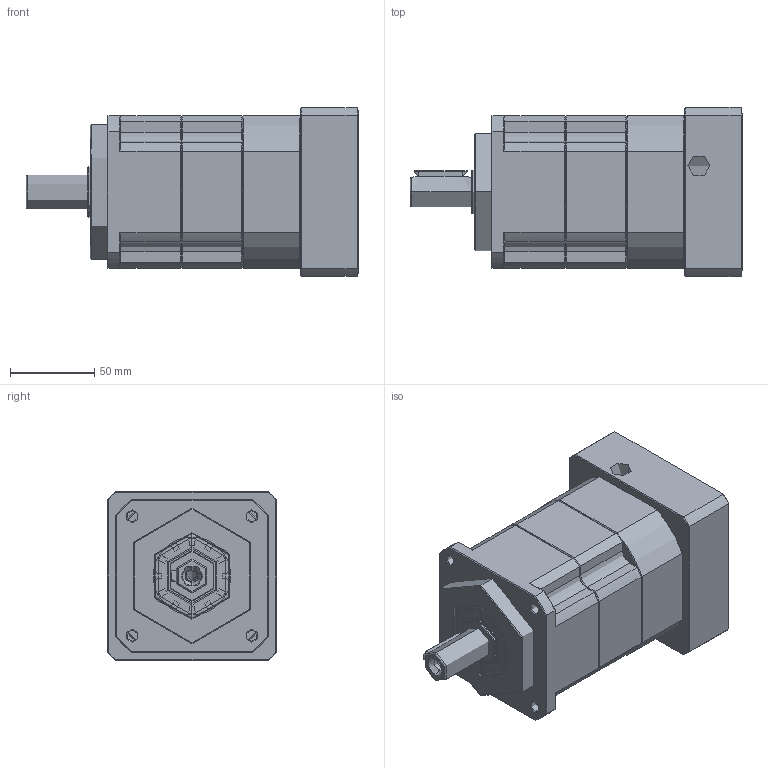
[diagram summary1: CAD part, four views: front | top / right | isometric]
STEP (ISO 10303-21) file: header records copied from the file, then geometry measured from it (millimetres).
FILE_DESCRIPTION (( 'STEP AP214' ), '1' );
FILE_NAME ('ZPB090-D20-L2-P1-19-95-115-M8.step', '2024-06-07T18:16:02', ( 'Windows 蚚誧' ), ( 'Organization' ), 'SwSTEP 2.0', 'SolidWorks 2016', '' );
FILE_SCHEMA (( 'AUTOMOTIVE_DESIGN' ));
Length unit declared in the file: millimetre
Products named in the file (1): ZPB090-D20-L2-P1-19-95-115-M8
Bounding box: 196.5 x 100 x 100 mm (x, y, z)
Topology: 0 solids, 37 shells, 1885 faces, 4977 edges, 3157 vertices
Faces by surface type: plane 969, bspline 387, cone 291, cylinder 236, torus 2
Full cylindrical faces by diameter (mm): 6.72 x1
Entity records: 96355 total; most frequent: CARTESIAN_POINT 48008, ORIENTED_EDGE 9905, DIRECTION 7691, EDGE_CURVE 4973, VECTOR 3273, LINE 3273, VERTEX_POINT 3155, AXIS2_PLACEMENT_3D 2209
One B-rep face of a CAD part: STEP entity #84038.
In plain terms, the planar face has unit normal (-1, 0, 0).
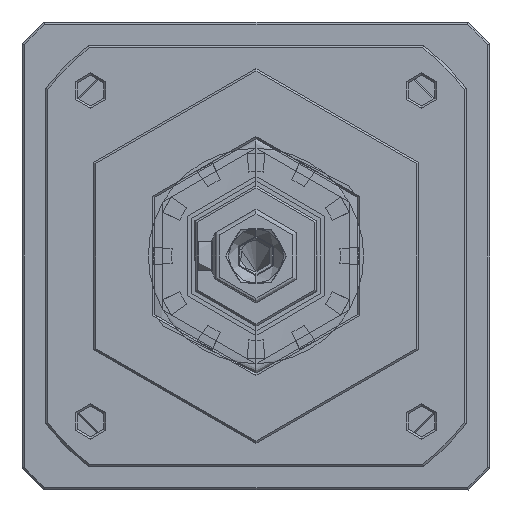
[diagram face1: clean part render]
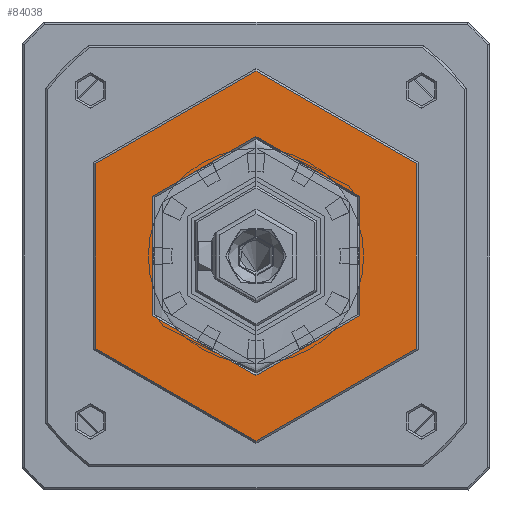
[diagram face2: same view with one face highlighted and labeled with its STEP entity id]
Its self-contained STEP definition (entity closure, numbers rounded to 3 decimals):
#39 = CARTESIAN_POINT ( 'NONE',  ( 0., 0., 25.5 ) ) ;
#2751 = DIRECTION ( 'NONE',  ( 0., 0., -1. ) ) ;
#6170 = CARTESIAN_POINT ( 'NONE',  ( 0., 0., -25.5 ) ) ;
#6382 = DIRECTION ( 'NONE',  ( 0., 0., -1. ) ) ;
#7079 = AXIS2_PLACEMENT_3D ( 'NONE', #30345, #38908, #76479 ) ;
#9382 = DIRECTION ( 'NONE',  ( -1., 0., 0. ) ) ;
#13712 = CARTESIAN_POINT ( 'NONE',  ( 0., 0., 0. ) ) ;
#15279 = EDGE_CURVE ( 'NONE', #36088, #32370, #39493, .T. ) ;
#15583 = CIRCLE ( 'NONE', #60520, 25.5 ) ;
#21239 = CARTESIAN_POINT ( 'NONE',  ( 0., -39.974, 39.974 ) ) ;
#21882 = EDGE_LOOP ( 'NONE', ( #38857, #82229 ) ) ;
#28915 = CARTESIAN_POINT ( 'NONE',  ( 0., 0., 0. ) ) ;
#29334 = EDGE_LOOP ( 'NONE', ( #42366, #30642 ) ) ;
#30345 = CARTESIAN_POINT ( 'NONE',  ( 0., 0., 0. ) ) ;
#30642 = ORIENTED_EDGE ( 'NONE', *, *, #73878, .F. ) ;
#32370 = VERTEX_POINT ( 'NONE', #82319 ) ;
#35837 = DIRECTION ( 'NONE',  ( 0., 0., -1. ) ) ;
#36088 = VERTEX_POINT ( 'NONE', #38172 ) ;
#38172 = CARTESIAN_POINT ( 'NONE',  ( 0., 0., -39.5 ) ) ;
#38857 = ORIENTED_EDGE ( 'NONE', *, *, #15279, .T. ) ;
#38908 = DIRECTION ( 'NONE',  ( -1., 0., 0. ) ) ;
#39493 = CIRCLE ( 'NONE', #45821, 39.5 ) ;
#42366 = ORIENTED_EDGE ( 'NONE', *, *, #92122, .F. ) ;
#45821 = AXIS2_PLACEMENT_3D ( 'NONE', #85859, #9382, #2751 ) ;
#45952 = VERTEX_POINT ( 'NONE', #6170 ) ;
#46385 = CIRCLE ( 'NONE', #7079, 25.5 ) ;
#57846 = AXIS2_PLACEMENT_3D ( 'NONE', #21239, #73360, #6382 ) ;
#60520 = AXIS2_PLACEMENT_3D ( 'NONE', #28915, #96229, #89595 ) ;
#60904 = FACE_BOUND ( 'NONE', #29334, .T. ) ;
#64447 = AXIS2_PLACEMENT_3D ( 'NONE', #13712, #66839, #35837 ) ;
#64909 = EDGE_CURVE ( 'NONE', #32370, #36088, #80745, .T. ) ;
#66839 = DIRECTION ( 'NONE',  ( -1., 0., 0. ) ) ;
#73360 = DIRECTION ( 'NONE',  ( 1., 0., 0. ) ) ;
#73878 = EDGE_CURVE ( 'NONE', #45952, #96966, #15583, .T. ) ;
#76479 = DIRECTION ( 'NONE',  ( 0., 0., 1. ) ) ;
#80745 = CIRCLE ( 'NONE', #64447, 39.5 ) ;
#82229 = ORIENTED_EDGE ( 'NONE', *, *, #64909, .T. ) ;
#82319 = CARTESIAN_POINT ( 'NONE',  ( 0., 0., 39.5 ) ) ;
#84038 = ADVANCED_FACE ( 'NONE', ( #60904, #95160 ), #93827, .F. ) ;
#85859 = CARTESIAN_POINT ( 'NONE',  ( 0., 0., 0. ) ) ;
#89595 = DIRECTION ( 'NONE',  ( 0., 0., 1. ) ) ;
#92122 = EDGE_CURVE ( 'NONE', #96966, #45952, #46385, .T. ) ;
#93827 = PLANE ( 'NONE',  #57846 ) ;
#95160 = FACE_OUTER_BOUND ( 'NONE', #21882, .T. ) ;
#96229 = DIRECTION ( 'NONE',  ( -1., 0., 0. ) ) ;
#96966 = VERTEX_POINT ( 'NONE', #39 ) ;
